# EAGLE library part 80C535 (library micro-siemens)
MICROPROCESSOR/PERIPHERAL DEVICE

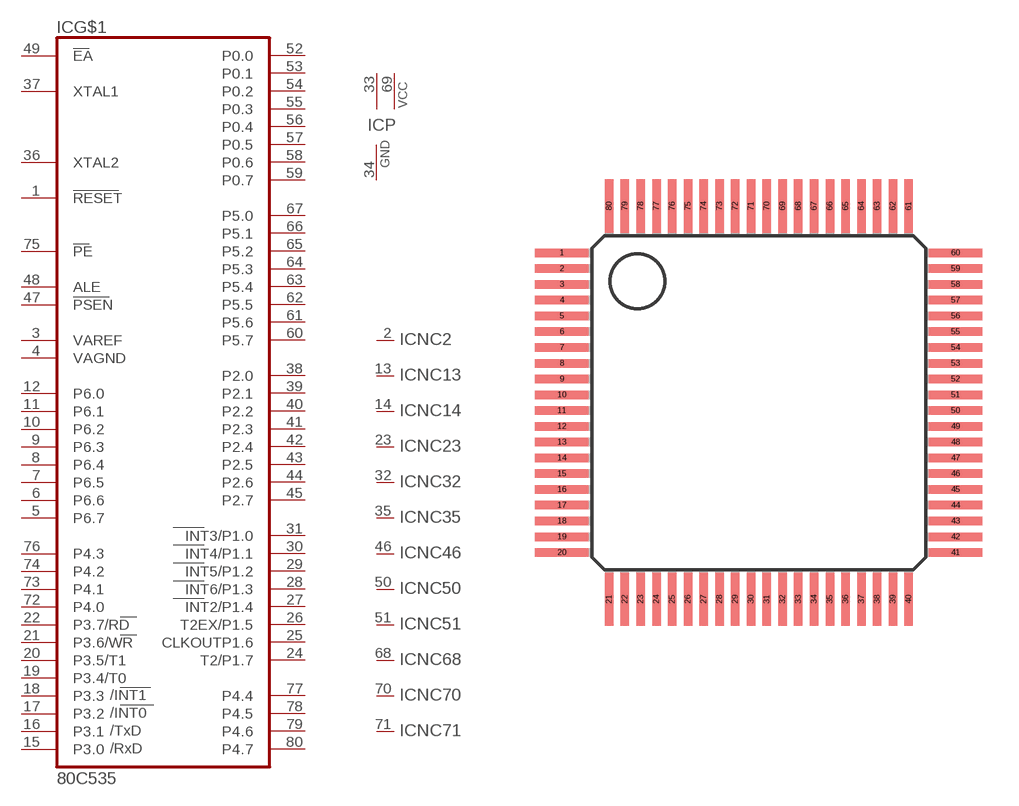
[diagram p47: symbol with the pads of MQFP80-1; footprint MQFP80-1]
Designator prefix IC; gates G$1=80C535 NC2=NC NC13=NC NC14=NC P=2VCC1GND NC23=NC NC32=NC NC35=NC NC46=NC NC50=NC NC51=NC NC68=NC NC70=NC NC71=NC

## 80C535  [MQFP80-1]
1  G$1:RESET  in
2  NC2:NC  nc
3  G$1:VAREF
4  G$1:VAGND
5  G$1:P6.7  in
6  G$1:P6.6  in
7  G$1:P6.5  in
8  G$1:P6.4  in
9  G$1:P6.3  in
10  G$1:P6.2  in
11  G$1:P6.1  in
12  G$1:P6.0  in
13  NC13:NC  nc
14  NC14:NC  nc
15  G$1:P3.0
16  G$1:P3.1
17  G$1:P3.2
18  G$1:P3.3
19  G$1:P3.4/T0
20  G$1:P3.5/T1
21  G$1:P3.6/WR
22  G$1:P3.7/RD
23  NC23:NC  nc
24  G$1:T2/P1.7
25  G$1:CLKOUTP1.6
26  G$1:T2EX/P1.5
27  G$1:INT2/P1.4
28  G$1:INT6/P1.3
29  G$1:INT5/P1.2
30  G$1:INT4/P1.1
31  G$1:INT3/P1.0
32  NC32:NC  nc
33  P:VCC  pwr
34  P:GND  pwr
35  NC35:NC  nc
36  G$1:XTAL2  in
37  G$1:XTAL1  in
38  G$1:P2.0
39  G$1:P2.1
40  G$1:P2.2
41  G$1:P2.3
42  G$1:P2.4
43  G$1:P2.5
44  G$1:P2.6
45  G$1:P2.7
46  NC46:NC  nc
47  G$1:PSEN  out
48  G$1:ALE  out
49  G$1:EA  in
50  NC50:NC  nc
51  NC51:NC  nc
52  G$1:P0.0
53  G$1:P0.1
54  G$1:P0.2
55  G$1:P0.3
56  G$1:P0.4
57  G$1:P0.5
58  G$1:P0.6
59  G$1:P0.7
60  G$1:P5.7
61  G$1:P5.6
62  G$1:P5.5
63  G$1:P5.4
64  G$1:P5.3
65  G$1:P5.2
66  G$1:P5.1
67  G$1:P5.0
68  NC68:NC  nc
69  P:VCC  pwr
70  NC70:NC  nc
71  NC71:NC  nc
72  G$1:P4.0
73  G$1:P4.1
74  G$1:P4.2
75  G$1:PE  in
76  G$1:P4.3
77  G$1:P4.4
78  G$1:P4.5
79  G$1:P4.6
80  G$1:P4.7

## Footprint MQFP80-1 (pad centres in mm)
Metric Quad Flat Pack
smd 2.2 x 0.35: 1 -8.125,6.175; 2 -8.125,5.525; 3 -8.125,4.875; 4 -8.125,4.225; 5 -8.125,3.575; 6 -8.125,2.925; 7 -8.125,2.275; 8 -8.125,1.625; 9 -8.125,0.975; 10 -8.125,0.325; 11 -8.125,-0.325; 12 -8.125,-0.975; 13 -8.125,-1.625; 14 -8.125,-2.275; 15 -8.125,-2.925; 16 -8.125,-3.575; 17 -8.125,-4.225; 18 -8.125,-4.875; 19 -8.125,-5.525; 20 -8.125,-6.175; 41 8.1,-6.175; 42 8.1,-5.525; 43 8.1,-4.875; 44 8.1,-4.225; 45 8.1,-3.575; 46 8.1,-2.925; 47 8.1,-2.275; 48 8.1,-1.625; 49 8.1,-0.975; 50 8.1,-0.325; 51 8.1,0.325; 52 8.1,0.975; 53 8.1,1.625; 54 8.1,2.275; 55 8.1,2.925; 56 8.1,3.575; 57 8.1,4.225; 58 8.1,4.875; 59 8.1,5.525; 60 8.1,6.175
smd 0.35 x 2.2: 21 -6.175,-8.1; 22 -5.525,-8.1; 23 -4.875,-8.1; 24 -4.225,-8.1; 25 -3.575,-8.1; 26 -2.925,-8.1; 27 -2.275,-8.1; 28 -1.625,-8.1; 29 -0.975,-8.1; 30 -0.325,-8.1; 31 0.325,-8.1; 32 0.975,-8.1; 33 1.625,-8.1; 34 2.275,-8.1; 35 2.925,-8.1; 36 3.575,-8.1; 37 4.225,-8.1; 38 4.875,-8.1; 39 5.525,-8.1; 40 6.175,-8.1; 61 6.175,8.1; 62 5.525,8.1; 63 4.875,8.1; 64 4.225,8.1; 65 3.575,8.1; 66 2.925,8.1; 67 2.275,8.1; 68 1.625,8.1; 69 0.975,8.1; 70 0.325,8.1; 71 -0.325,8.1; 72 -0.975,8.1; 73 -1.625,8.1; 74 -2.275,8.1; 75 -2.925,8.1; 76 -3.575,8.1; 77 -4.225,8.1; 78 -4.875,8.1; 79 -5.525,8.1; 80 -6.175,8.1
